VERSION 5.8 ;
BUSBITCHARS "[]" ;
DIVIDERCHAR "/" ;
UNITS
    DATABASE MICRONS 1000 ;
END UNITS

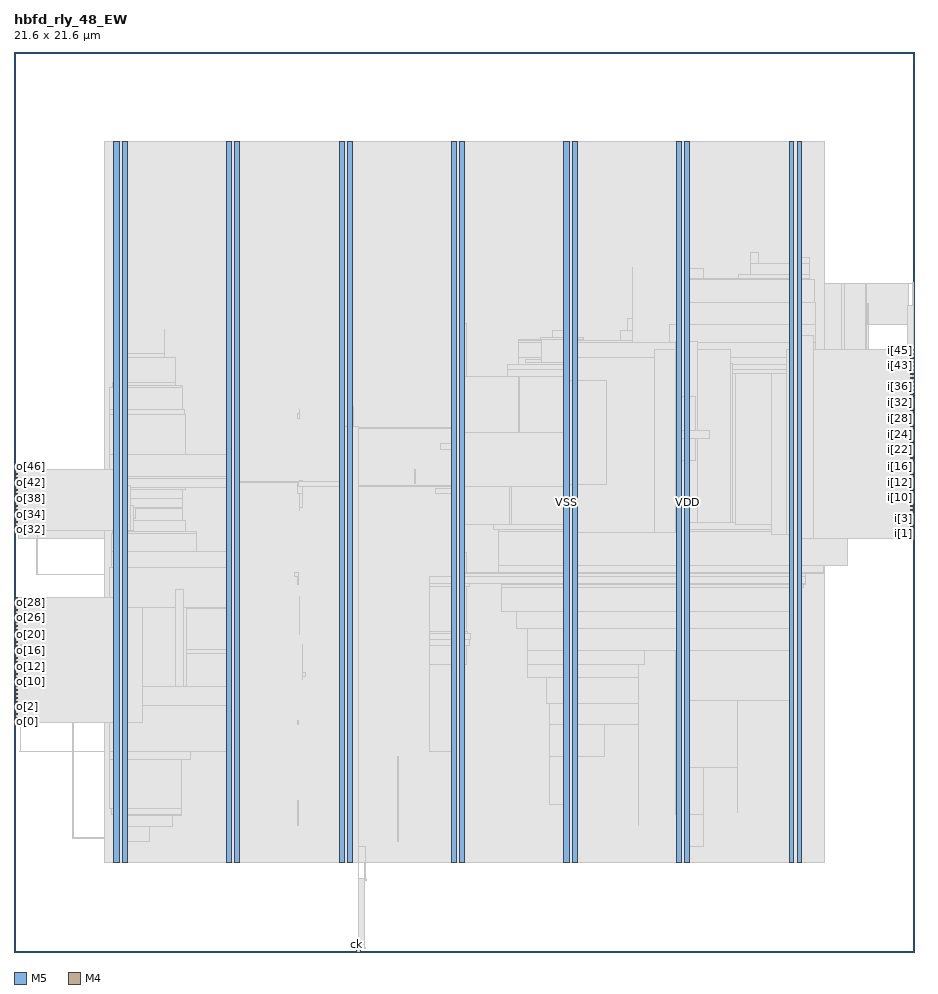
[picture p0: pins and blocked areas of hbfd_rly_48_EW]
MACRO hbfd_rly_48_EW
  FOREIGN hbfd_rly_48_EW 0 0 ;
  CLASS BLOCK ;
  SIZE 21.6 BY 21.6 ;
  PIN ck
    DIRECTION INPUT ;
    USE SIGNAL ;
    PORT
      LAYER M5 ;
        RECT  8.208 0 8.232 0.084 ;
    END
  END ck
  PIN i[0]
    DIRECTION INPUT ;
    USE SIGNAL ;
    PORT
      LAYER M4 ;
        RECT  21.516 9.936 21.6 9.96 ;
    END
  END i[0]
  PIN i[10]
    DIRECTION INPUT ;
    USE SIGNAL ;
    PORT
      LAYER M4 ;
        RECT  21.516 10.896 21.6 10.92 ;
    END
  END i[10]
  PIN i[11]
    DIRECTION INPUT ;
    USE SIGNAL ;
    PORT
      LAYER M4 ;
        RECT  21.516 10.992 21.6 11.016 ;
    END
  END i[11]
  PIN i[12]
    DIRECTION INPUT ;
    USE SIGNAL ;
    PORT
      LAYER M4 ;
        RECT  21.516 11.088 21.6 11.112 ;
    END
  END i[12]
  PIN i[13]
    DIRECTION INPUT ;
    USE SIGNAL ;
    PORT
      LAYER M4 ;
        RECT  21.516 11.184 21.6 11.208 ;
    END
  END i[13]
  PIN i[14]
    DIRECTION INPUT ;
    USE SIGNAL ;
    PORT
      LAYER M4 ;
        RECT  21.516 11.28 21.6 11.304 ;
    END
  END i[14]
  PIN i[15]
    DIRECTION INPUT ;
    USE SIGNAL ;
    PORT
      LAYER M4 ;
        RECT  21.516 11.376 21.6 11.4 ;
    END
  END i[15]
  PIN i[16]
    DIRECTION INPUT ;
    USE SIGNAL ;
    PORT
      LAYER M4 ;
        RECT  21.516 11.472 21.6 11.496 ;
    END
  END i[16]
  PIN i[17]
    DIRECTION INPUT ;
    USE SIGNAL ;
    PORT
      LAYER M4 ;
        RECT  21.516 11.568 21.6 11.592 ;
    END
  END i[17]
  PIN i[18]
    DIRECTION INPUT ;
    USE SIGNAL ;
    PORT
      LAYER M4 ;
        RECT  21.516 11.664 21.6 11.688 ;
    END
  END i[18]
  PIN i[19]
    DIRECTION INPUT ;
    USE SIGNAL ;
    PORT
      LAYER M4 ;
        RECT  21.516 11.76 21.6 11.784 ;
    END
  END i[19]
  PIN i[1]
    DIRECTION INPUT ;
    USE SIGNAL ;
    PORT
      LAYER M4 ;
        RECT  21.516 10.032 21.6 10.056 ;
    END
  END i[1]
  PIN i[20]
    DIRECTION INPUT ;
    USE SIGNAL ;
    PORT
      LAYER M4 ;
        RECT  21.516 11.856 21.6 11.88 ;
    END
  END i[20]
  PIN i[21]
    DIRECTION INPUT ;
    USE SIGNAL ;
    PORT
      LAYER M4 ;
        RECT  21.516 11.952 21.6 11.976 ;
    END
  END i[21]
  PIN i[22]
    DIRECTION INPUT ;
    USE SIGNAL ;
    PORT
      LAYER M4 ;
        RECT  21.516 12.048 21.6 12.072 ;
    END
  END i[22]
  PIN i[23]
    DIRECTION INPUT ;
    USE SIGNAL ;
    PORT
      LAYER M4 ;
        RECT  21.516 12.144 21.6 12.168 ;
    END
  END i[23]
  PIN i[24]
    DIRECTION INPUT ;
    USE SIGNAL ;
    PORT
      LAYER M4 ;
        RECT  21.516 12.24 21.6 12.264 ;
    END
  END i[24]
  PIN i[25]
    DIRECTION INPUT ;
    USE SIGNAL ;
    PORT
      LAYER M4 ;
        RECT  21.516 12.336 21.6 12.36 ;
    END
  END i[25]
  PIN i[26]
    DIRECTION INPUT ;
    USE SIGNAL ;
    PORT
      LAYER M4 ;
        RECT  21.516 12.432 21.6 12.456 ;
    END
  END i[26]
  PIN i[27]
    DIRECTION INPUT ;
    USE SIGNAL ;
    PORT
      LAYER M4 ;
        RECT  21.516 12.528 21.6 12.552 ;
    END
  END i[27]
  PIN i[28]
    DIRECTION INPUT ;
    USE SIGNAL ;
    PORT
      LAYER M4 ;
        RECT  21.516 12.624 21.6 12.648 ;
    END
  END i[28]
  PIN i[29]
    DIRECTION INPUT ;
    USE SIGNAL ;
    PORT
      LAYER M4 ;
        RECT  21.516 12.72 21.6 12.744 ;
    END
  END i[29]
  PIN i[2]
    DIRECTION INPUT ;
    USE SIGNAL ;
    PORT
      LAYER M4 ;
        RECT  21.516 10.128 21.6 10.152 ;
    END
  END i[2]
  PIN i[30]
    DIRECTION INPUT ;
    USE SIGNAL ;
    PORT
      LAYER M4 ;
        RECT  21.516 12.816 21.6 12.84 ;
    END
  END i[30]
  PIN i[31]
    DIRECTION INPUT ;
    USE SIGNAL ;
    PORT
      LAYER M4 ;
        RECT  21.516 12.912 21.6 12.936 ;
    END
  END i[31]
  PIN i[32]
    DIRECTION INPUT ;
    USE SIGNAL ;
    PORT
      LAYER M4 ;
        RECT  21.516 13.008 21.6 13.032 ;
    END
  END i[32]
  PIN i[33]
    DIRECTION INPUT ;
    USE SIGNAL ;
    PORT
      LAYER M4 ;
        RECT  21.516 13.104 21.6 13.128 ;
    END
  END i[33]
  PIN i[34]
    DIRECTION INPUT ;
    USE SIGNAL ;
    PORT
      LAYER M4 ;
        RECT  21.516 13.2 21.6 13.224 ;
    END
  END i[34]
  PIN i[35]
    DIRECTION INPUT ;
    USE SIGNAL ;
    PORT
      LAYER M4 ;
        RECT  21.516 13.296 21.6 13.32 ;
    END
  END i[35]
  PIN i[36]
    DIRECTION INPUT ;
    USE SIGNAL ;
    PORT
      LAYER M4 ;
        RECT  21.516 13.392 21.6 13.416 ;
    END
  END i[36]
  PIN i[37]
    DIRECTION INPUT ;
    USE SIGNAL ;
    PORT
      LAYER M4 ;
        RECT  21.516 13.488 21.6 13.512 ;
    END
  END i[37]
  PIN i[38]
    DIRECTION INPUT ;
    USE SIGNAL ;
    PORT
      LAYER M4 ;
        RECT  21.516 13.584 21.6 13.608 ;
    END
  END i[38]
  PIN i[39]
    DIRECTION INPUT ;
    USE SIGNAL ;
    PORT
      LAYER M4 ;
        RECT  21.516 13.68 21.6 13.704 ;
    END
  END i[39]
  PIN i[3]
    DIRECTION INPUT ;
    USE SIGNAL ;
    PORT
      LAYER M4 ;
        RECT  21.516 10.224 21.6 10.248 ;
    END
  END i[3]
  PIN i[40]
    DIRECTION INPUT ;
    USE SIGNAL ;
    PORT
      LAYER M4 ;
        RECT  21.516 13.776 21.6 13.8 ;
    END
  END i[40]
  PIN i[41]
    DIRECTION INPUT ;
    USE SIGNAL ;
    PORT
      LAYER M4 ;
        RECT  21.516 13.872 21.6 13.896 ;
    END
  END i[41]
  PIN i[42]
    DIRECTION INPUT ;
    USE SIGNAL ;
    PORT
      LAYER M4 ;
        RECT  21.516 13.968 21.6 13.992 ;
    END
  END i[42]
  PIN i[43]
    DIRECTION INPUT ;
    USE SIGNAL ;
    PORT
      LAYER M4 ;
        RECT  21.516 14.064 21.6 14.088 ;
    END
  END i[43]
  PIN i[44]
    DIRECTION INPUT ;
    USE SIGNAL ;
    PORT
      LAYER M4 ;
        RECT  21.516 14.16 21.6 14.184 ;
    END
  END i[44]
  PIN i[45]
    DIRECTION INPUT ;
    USE SIGNAL ;
    PORT
      LAYER M4 ;
        RECT  21.516 14.256 21.6 14.28 ;
    END
  END i[45]
  PIN i[46]
    DIRECTION INPUT ;
    USE SIGNAL ;
    PORT
      LAYER M4 ;
        RECT  21.516 14.352 21.6 14.376 ;
    END
  END i[46]
  PIN i[47]
    DIRECTION INPUT ;
    USE SIGNAL ;
    PORT
      LAYER M4 ;
        RECT  21.516 14.448 21.6 14.472 ;
    END
  END i[47]
  PIN i[4]
    DIRECTION INPUT ;
    USE SIGNAL ;
    PORT
      LAYER M4 ;
        RECT  21.516 10.32 21.6 10.344 ;
    END
  END i[4]
  PIN i[5]
    DIRECTION INPUT ;
    USE SIGNAL ;
    PORT
      LAYER M4 ;
        RECT  21.516 10.416 21.6 10.44 ;
    END
  END i[5]
  PIN i[6]
    DIRECTION INPUT ;
    USE SIGNAL ;
    PORT
      LAYER M4 ;
        RECT  21.516 10.512 21.6 10.536 ;
    END
  END i[6]
  PIN i[7]
    DIRECTION INPUT ;
    USE SIGNAL ;
    PORT
      LAYER M4 ;
        RECT  21.516 10.608 21.6 10.632 ;
    END
  END i[7]
  PIN i[8]
    DIRECTION INPUT ;
    USE SIGNAL ;
    PORT
      LAYER M4 ;
        RECT  21.516 10.704 21.6 10.728 ;
    END
  END i[8]
  PIN i[9]
    DIRECTION INPUT ;
    USE SIGNAL ;
    PORT
      LAYER M4 ;
        RECT  21.516 10.8 21.6 10.824 ;
    END
  END i[9]
  PIN o[0]
    DIRECTION OUTPUT ;
    USE SIGNAL ;
    PORT
      LAYER M4 ;
        RECT  0 5.52 0.084 5.544 ;
    END
  END o[0]
  PIN o[10]
    DIRECTION OUTPUT ;
    USE SIGNAL ;
    PORT
      LAYER M4 ;
        RECT  0 6.48 0.084 6.504 ;
    END
  END o[10]
  PIN o[11]
    DIRECTION OUTPUT ;
    USE SIGNAL ;
    PORT
      LAYER M4 ;
        RECT  0 6.576 0.084 6.6 ;
    END
  END o[11]
  PIN o[12]
    DIRECTION OUTPUT ;
    USE SIGNAL ;
    PORT
      LAYER M4 ;
        RECT  0 6.672 0.084 6.696 ;
    END
  END o[12]
  PIN o[13]
    DIRECTION OUTPUT ;
    USE SIGNAL ;
    PORT
      LAYER M4 ;
        RECT  0 6.768 0.084 6.792 ;
    END
  END o[13]
  PIN o[14]
    DIRECTION OUTPUT ;
    USE SIGNAL ;
    PORT
      LAYER M4 ;
        RECT  0 6.864 0.084 6.888 ;
    END
  END o[14]
  PIN o[15]
    DIRECTION OUTPUT ;
    USE SIGNAL ;
    PORT
      LAYER M4 ;
        RECT  0 6.96 0.084 6.984 ;
    END
  END o[15]
  PIN o[16]
    DIRECTION OUTPUT ;
    USE SIGNAL ;
    PORT
      LAYER M4 ;
        RECT  0 7.056 0.084 7.08 ;
    END
  END o[16]
  PIN o[17]
    DIRECTION OUTPUT ;
    USE SIGNAL ;
    PORT
      LAYER M4 ;
        RECT  0 7.152 0.084 7.176 ;
    END
  END o[17]
  PIN o[18]
    DIRECTION OUTPUT ;
    USE SIGNAL ;
    PORT
      LAYER M4 ;
        RECT  0 7.248 0.084 7.272 ;
    END
  END o[18]
  PIN o[19]
    DIRECTION OUTPUT ;
    USE SIGNAL ;
    PORT
      LAYER M4 ;
        RECT  0 7.344 0.084 7.368 ;
    END
  END o[19]
  PIN o[1]
    DIRECTION OUTPUT ;
    USE SIGNAL ;
    PORT
      LAYER M4 ;
        RECT  0 5.616 0.084 5.64 ;
    END
  END o[1]
  PIN o[20]
    DIRECTION OUTPUT ;
    USE SIGNAL ;
    PORT
      LAYER M4 ;
        RECT  0 7.44 0.084 7.464 ;
    END
  END o[20]
  PIN o[21]
    DIRECTION OUTPUT ;
    USE SIGNAL ;
    PORT
      LAYER M4 ;
        RECT  0 7.536 0.084 7.56 ;
    END
  END o[21]
  PIN o[22]
    DIRECTION OUTPUT ;
    USE SIGNAL ;
    PORT
      LAYER M4 ;
        RECT  0 7.632 0.084 7.656 ;
    END
  END o[22]
  PIN o[23]
    DIRECTION OUTPUT ;
    USE SIGNAL ;
    PORT
      LAYER M4 ;
        RECT  0 7.728 0.084 7.752 ;
    END
  END o[23]
  PIN o[24]
    DIRECTION OUTPUT ;
    USE SIGNAL ;
    PORT
      LAYER M4 ;
        RECT  0 7.824 0.084 7.848 ;
    END
  END o[24]
  PIN o[25]
    DIRECTION OUTPUT ;
    USE SIGNAL ;
    PORT
      LAYER M4 ;
        RECT  0 7.92 0.084 7.944 ;
    END
  END o[25]
  PIN o[26]
    DIRECTION OUTPUT ;
    USE SIGNAL ;
    PORT
      LAYER M4 ;
        RECT  0 8.016 0.084 8.04 ;
    END
  END o[26]
  PIN o[27]
    DIRECTION OUTPUT ;
    USE SIGNAL ;
    PORT
      LAYER M4 ;
        RECT  0 8.112 0.084 8.136 ;
    END
  END o[27]
  PIN o[28]
    DIRECTION OUTPUT ;
    USE SIGNAL ;
    PORT
      LAYER M4 ;
        RECT  0 8.208 0.084 8.232 ;
    END
  END o[28]
  PIN o[29]
    DIRECTION OUTPUT ;
    USE SIGNAL ;
    PORT
      LAYER M4 ;
        RECT  0 8.304 0.084 8.328 ;
    END
  END o[29]
  PIN o[2]
    DIRECTION OUTPUT ;
    USE SIGNAL ;
    PORT
      LAYER M4 ;
        RECT  0 5.712 0.084 5.736 ;
    END
  END o[2]
  PIN o[30]
    DIRECTION OUTPUT ;
    USE SIGNAL ;
    PORT
      LAYER M4 ;
        RECT  0 8.4 0.084 8.424 ;
    END
  END o[30]
  PIN o[31]
    DIRECTION OUTPUT ;
    USE SIGNAL ;
    PORT
      LAYER M4 ;
        RECT  0 8.496 0.084 8.52 ;
    END
  END o[31]
  PIN o[32]
    DIRECTION OUTPUT ;
    USE SIGNAL ;
    PORT
      LAYER M4 ;
        RECT  0 10.128 0.084 10.152 ;
    END
  END o[32]
  PIN o[33]
    DIRECTION OUTPUT ;
    USE SIGNAL ;
    PORT
      LAYER M4 ;
        RECT  0 10.224 0.084 10.248 ;
    END
  END o[33]
  PIN o[34]
    DIRECTION OUTPUT ;
    USE SIGNAL ;
    PORT
      LAYER M4 ;
        RECT  0 10.32 0.084 10.344 ;
    END
  END o[34]
  PIN o[35]
    DIRECTION OUTPUT ;
    USE SIGNAL ;
    PORT
      LAYER M4 ;
        RECT  0 10.416 0.084 10.44 ;
    END
  END o[35]
  PIN o[36]
    DIRECTION OUTPUT ;
    USE SIGNAL ;
    PORT
      LAYER M4 ;
        RECT  0 10.512 0.084 10.536 ;
    END
  END o[36]
  PIN o[37]
    DIRECTION OUTPUT ;
    USE SIGNAL ;
    PORT
      LAYER M4 ;
        RECT  0 10.608 0.084 10.632 ;
    END
  END o[37]
  PIN o[38]
    DIRECTION OUTPUT ;
    USE SIGNAL ;
    PORT
      LAYER M4 ;
        RECT  0 10.704 0.084 10.728 ;
    END
  END o[38]
  PIN o[39]
    DIRECTION OUTPUT ;
    USE SIGNAL ;
    PORT
      LAYER M4 ;
        RECT  0 10.8 0.084 10.824 ;
    END
  END o[39]
  PIN o[3]
    DIRECTION OUTPUT ;
    USE SIGNAL ;
    PORT
      LAYER M4 ;
        RECT  0 5.808 0.084 5.832 ;
    END
  END o[3]
  PIN o[40]
    DIRECTION OUTPUT ;
    USE SIGNAL ;
    PORT
      LAYER M4 ;
        RECT  0 10.896 0.084 10.92 ;
    END
  END o[40]
  PIN o[41]
    DIRECTION OUTPUT ;
    USE SIGNAL ;
    PORT
      LAYER M4 ;
        RECT  0 10.992 0.084 11.016 ;
    END
  END o[41]
  PIN o[42]
    DIRECTION OUTPUT ;
    USE SIGNAL ;
    PORT
      LAYER M4 ;
        RECT  0 11.088 0.084 11.112 ;
    END
  END o[42]
  PIN o[43]
    DIRECTION OUTPUT ;
    USE SIGNAL ;
    PORT
      LAYER M4 ;
        RECT  0 11.184 0.084 11.208 ;
    END
  END o[43]
  PIN o[44]
    DIRECTION OUTPUT ;
    USE SIGNAL ;
    PORT
      LAYER M4 ;
        RECT  0 11.28 0.084 11.304 ;
    END
  END o[44]
  PIN o[45]
    DIRECTION OUTPUT ;
    USE SIGNAL ;
    PORT
      LAYER M4 ;
        RECT  0 11.376 0.084 11.4 ;
    END
  END o[45]
  PIN o[46]
    DIRECTION OUTPUT ;
    USE SIGNAL ;
    PORT
      LAYER M4 ;
        RECT  0 11.472 0.084 11.496 ;
    END
  END o[46]
  PIN o[47]
    DIRECTION OUTPUT ;
    USE SIGNAL ;
    PORT
      LAYER M4 ;
        RECT  0 11.568 0.084 11.592 ;
    END
  END o[47]
  PIN o[4]
    DIRECTION OUTPUT ;
    USE SIGNAL ;
    PORT
      LAYER M4 ;
        RECT  0 5.904 0.084 5.928 ;
    END
  END o[4]
  PIN o[5]
    DIRECTION OUTPUT ;
    USE SIGNAL ;
    PORT
      LAYER M4 ;
        RECT  0 6 0.084 6.024 ;
    END
  END o[5]
  PIN o[6]
    DIRECTION OUTPUT ;
    USE SIGNAL ;
    PORT
      LAYER M4 ;
        RECT  0 6.096 0.084 6.12 ;
    END
  END o[6]
  PIN o[7]
    DIRECTION OUTPUT ;
    USE SIGNAL ;
    PORT
      LAYER M4 ;
        RECT  0 6.192 0.084 6.216 ;
    END
  END o[7]
  PIN o[8]
    DIRECTION OUTPUT ;
    USE SIGNAL ;
    PORT
      LAYER M4 ;
        RECT  0 6.288 0.084 6.312 ;
    END
  END o[8]
  PIN o[9]
    DIRECTION OUTPUT ;
    USE SIGNAL ;
    PORT
      LAYER M4 ;
        RECT  0 6.384 0.084 6.408 ;
    END
  END o[9]
  PIN rs
    DIRECTION INPUT ;
    USE SIGNAL ;
    PORT
      LAYER M5 ;
        RECT  8.304 0 8.328 0.084 ;
    END
  END rs
  PIN VDD
    DIRECTION INOUT ;
    USE POWER ;
    PORT
      LAYER M5 ;
        RECT  18.792 2.151 18.912 19.449 ;
        RECT  16.092 2.151 16.212 19.449 ;
        RECT  13.392 2.151 13.512 19.449 ;
        RECT  10.692 2.151 10.812 19.449 ;
        RECT  7.992 2.151 8.112 19.449 ;
        RECT  5.292 2.151 5.412 19.449 ;
        RECT  2.592 2.151 2.712 19.449 ;
    END
  END VDD
  PIN VSS
    DIRECTION INOUT ;
    USE GROUND ;
    PORT
      LAYER M5 ;
        RECT  18.6 2.137 18.72 19.463 ;
        RECT  15.9 2.137 16.02 19.463 ;
        RECT  13.2 2.137 13.32 19.463 ;
        RECT  10.5 2.137 10.62 19.463 ;
        RECT  7.8 2.137 7.92 19.463 ;
        RECT  5.1 2.137 5.22 19.463 ;
        RECT  2.4 2.137 2.52 19.463 ;
    END
  END VSS
  # OT_OBS_CLOSED layer=M5 d_um=1.536 added=5
  OBS
    LAYER RVTN ;
     RECT  2.16 2.16 19.44 2.295 ;
     RECT  2.16 2.565 19.44 2.835 ;
     RECT  2.16 3.105 19.44 3.375 ;
     RECT  2.16 3.645 19.44 3.915 ;
     RECT  2.16 4.185 19.44 4.455 ;
     RECT  2.16 4.725 19.44 4.995 ;
     RECT  2.16 5.265 19.44 5.535 ;
     RECT  2.16 5.805 19.44 6.075 ;
     RECT  2.16 6.345 19.44 6.615 ;
     RECT  2.16 6.885 19.44 7.155 ;
     RECT  2.16 7.425 19.44 7.695 ;
     RECT  2.16 7.965 19.44 8.235 ;
     RECT  2.16 8.505 19.44 8.775 ;
     RECT  2.16 9.045 19.44 9.315 ;
     RECT  2.16 9.585 19.44 9.855 ;
     RECT  2.16 10.125 19.44 10.395 ;
     RECT  2.16 10.665 19.44 10.935 ;
     RECT  2.16 11.205 19.44 11.475 ;
     RECT  2.16 11.745 19.44 12.015 ;
     RECT  2.16 12.285 19.44 12.555 ;
     RECT  2.16 12.825 19.44 13.095 ;
     RECT  2.16 13.365 19.44 13.635 ;
     RECT  2.16 13.905 19.44 14.175 ;
     RECT  2.16 14.445 19.44 14.715 ;
     RECT  2.16 14.985 19.44 15.255 ;
     RECT  2.16 15.525 19.44 15.795 ;
     RECT  2.16 16.065 19.44 16.335 ;
     RECT  2.16 16.605 19.44 16.875 ;
     RECT  2.16 17.145 19.44 17.415 ;
     RECT  2.16 17.685 19.44 17.955 ;
     RECT  2.16 18.225 19.44 18.495 ;
     RECT  2.16 18.765 19.44 19.035 ;
     RECT  2.16 19.305 19.44 19.44 ;
    LAYER RVTP ;
     RECT  2.16 2.295 19.44 2.565 ;
     RECT  2.16 2.835 19.44 3.105 ;
     RECT  2.16 3.375 19.44 3.645 ;
     RECT  2.16 3.915 19.44 4.185 ;
     RECT  2.16 4.455 19.44 4.725 ;
     RECT  2.16 4.995 19.44 5.265 ;
     RECT  2.16 5.535 19.44 5.805 ;
     RECT  2.16 6.075 19.44 6.345 ;
     RECT  2.16 6.615 19.44 6.885 ;
     RECT  2.16 7.155 19.44 7.425 ;
     RECT  2.16 7.695 19.44 7.965 ;
     RECT  2.16 8.235 19.44 8.505 ;
     RECT  2.16 8.775 19.44 9.045 ;
     RECT  2.16 9.315 19.44 9.585 ;
     RECT  2.16 9.855 19.44 10.125 ;
     RECT  2.16 10.395 19.44 10.665 ;
     RECT  2.16 10.935 19.44 11.205 ;
     RECT  2.16 11.475 19.44 11.745 ;
     RECT  2.16 12.015 19.44 12.285 ;
     RECT  2.16 12.555 19.44 12.825 ;
     RECT  2.16 13.095 19.44 13.365 ;
     RECT  2.16 13.635 19.44 13.905 ;
     RECT  2.16 14.175 19.44 14.445 ;
     RECT  2.16 14.715 19.44 14.985 ;
     RECT  2.16 15.255 19.44 15.525 ;
     RECT  2.16 15.795 19.44 16.065 ;
     RECT  2.16 16.335 19.44 16.605 ;
     RECT  2.16 16.875 19.44 17.145 ;
     RECT  2.16 17.415 19.44 17.685 ;
     RECT  2.16 17.955 19.44 18.225 ;
     RECT  2.16 18.495 19.44 18.765 ;
     RECT  2.16 19.035 19.44 19.305 ;
    LAYER M1 ;
     RECT  2.16 2.151 19.44 19.449 ;
    LAYER M2 ;
     RECT  0.463 6.084 0.535 6.444 ;
     RECT  0.103 9.936 0.535 9.954 ;
     RECT  1.399 2.736 2.16 2.754 ;
     RECT  0.139 4.806 2.16 4.824 ;
     RECT  0.535 5.616 2.16 6.444 ;
     RECT  0.535 7.326 2.16 7.794 ;
     RECT  0.535 9.054 2.16 9.072 ;
     RECT  0.535 9.936 2.16 10.224 ;
     RECT  2.16 2.151 19.44 19.449 ;
     RECT  19.44 9.288 19.859 16.056 ;
     RECT  19.859 13.878 19.931 16.056 ;
     RECT  19.859 9.288 19.967 13.05 ;
     RECT  19.967 9.288 20.003 9.306 ;
     RECT  19.967 10.098 20.003 13.05 ;
     RECT  20.003 10.98 20.435 13.05 ;
     RECT  19.931 14.184 20.435 16.056 ;
     RECT  20.435 12.528 20.471 13.05 ;
     RECT  20.435 15.03 20.471 16.056 ;
     RECT  20.471 12.528 20.507 12.924 ;
     RECT  20.003 10.098 20.543 10.116 ;
     RECT  20.435 10.98 20.543 11.574 ;
     RECT  20.507 12.87 20.543 12.888 ;
     RECT  20.435 14.184 21.479 14.202 ;
     RECT  20.471 15.066 21.479 16.056 ;
     RECT  20.543 11.52 21.515 11.538 ;
     RECT  21.479 15.066 21.515 15.084 ;
     RECT  21.487 13.41 21.587 13.428 ;
     RECT  21.479 16.038 21.587 16.056 ;
    LAYER M3 ;
     RECT  8.424 1.723 8.442 2.143 ;
     RECT  2.415 2.143 2.505 2.413 ;
     RECT  5.115 2.143 5.205 2.413 ;
     RECT  10.515 2.143 10.605 2.413 ;
     RECT  13.215 2.143 13.305 2.413 ;
     RECT  15.915 2.143 16.005 2.413 ;
     RECT  18.615 2.143 18.705 2.413 ;
     RECT  7.815 2.143 8.442 2.525 ;
     RECT  15.915 2.413 16.197 2.533 ;
     RECT  2.415 2.413 2.697 2.641 ;
     RECT  2.415 2.641 3.258 3.001 ;
     RECT  2.415 3.001 3.798 3.271 ;
     RECT  2.415 3.271 4.014 3.307 ;
     RECT  15.915 2.533 16.542 3.307 ;
     RECT  2.34 3.307 4.014 3.451 ;
     RECT  13.215 2.413 13.497 3.541 ;
     RECT  6.804 3.037 6.822 3.641 ;
     RECT  15.876 3.307 16.542 4.423 ;
     RECT  17.352 3.343 17.37 4.423 ;
     RECT  2.304 3.451 4.014 4.621 ;
     RECT  9.216 2.641 9.234 4.685 ;
     RECT  12.852 3.541 13.497 4.693 ;
     RECT  2.304 4.621 4.23 4.801 ;
     RECT  5.115 2.413 5.397 4.801 ;
     RECT  10.515 2.413 10.797 4.801 ;
     RECT  12.852 4.693 14.166 5.467 ;
     RECT  14.976 3.037 14.994 5.467 ;
     RECT  6.804 5.467 6.822 5.567 ;
     RECT  0.144 4.801 0.162 5.611 ;
     RECT  1.404 2.731 1.422 5.645 ;
     RECT  2.304 4.801 5.397 5.909 ;
     RECT  12.852 5.467 14.994 5.971 ;
     RECT  0.144 5.611 0.558 6.029 ;
     RECT  15.876 4.423 17.37 6.043 ;
     RECT  18.615 2.413 18.897 6.043 ;
     RECT  0.468 6.029 0.558 6.509 ;
     RECT  12.78 5.971 14.994 6.583 ;
     RECT  6.912 6.547 6.93 6.619 ;
     RECT  2.34 5.909 5.397 6.667 ;
     RECT  6.912 6.619 7.002 6.719 ;
     RECT  9.972 4.801 10.797 6.889 ;
     RECT  12.312 6.583 14.994 6.889 ;
     RECT  2.304 6.667 5.397 7.051 ;
     RECT  12.312 6.889 15.138 7.231 ;
     RECT  15.876 6.043 18.897 7.231 ;
     RECT  0.468 6.509 0.522 7.243 ;
     RECT  2.268 7.051 5.397 7.259 ;
     RECT  0.324 7.243 0.522 7.321 ;
     RECT  9.972 6.889 10.854 7.357 ;
     RECT  0.324 7.321 0.558 7.373 ;
     RECT  6.912 6.719 6.93 7.385 ;
     RECT  9.972 7.357 10.926 7.501 ;
     RECT  9.972 7.501 10.962 7.655 ;
     RECT  9.972 7.655 10.89 7.7 ;
     RECT  12.312 7.231 18.897 7.771 ;
     RECT  0.54 7.373 0.558 8.045 ;
     RECT  12.06 7.771 18.897 8.167 ;
     RECT  0.144 8.107 0.162 8.285 ;
     RECT  6.84 7.627 6.858 8.537 ;
     RECT  11.7 8.167 18.897 8.743 ;
     RECT  9.972 7.7 10.854 8.779 ;
     RECT  11.7 8.743 18.954 8.815 ;
     RECT  9.972 8.779 10.926 8.851 ;
     RECT  11.7 8.815 18.99 8.851 ;
     RECT  9.972 8.851 18.99 9.005 ;
     RECT  6.804 8.815 6.822 9.013 ;
     RECT  10.515 9.005 18.99 9.085 ;
     RECT  6.732 9.013 6.822 9.113 ;
     RECT  10.515 9.085 19.422 9.113 ;
     RECT  2.304 7.259 5.397 9.239 ;
     RECT  11.628 9.113 19.422 9.283 ;
     RECT  10.515 9.113 10.854 9.581 ;
     RECT  2.34 9.239 5.397 9.617 ;
     RECT  0.54 9.049 0.558 9.931 ;
     RECT  2.34 9.617 4.374 10.049 ;
     RECT  2.376 10.049 4.374 10.085 ;
     RECT  11.628 9.283 19.998 10.093 ;
     RECT  0.108 9.931 0.558 10.123 ;
     RECT  11.628 10.093 20.538 10.129 ;
     RECT  0.108 10.123 0.666 10.253 ;
     RECT  0.108 10.253 0.558 10.349 ;
     RECT  2.376 10.085 4.122 10.355 ;
     RECT  10.515 9.581 10.797 10.561 ;
     RECT  11.52 10.129 20.538 10.561 ;
     RECT  0.144 10.349 0.558 10.637 ;
     RECT  6.84 10.597 6.858 10.669 ;
     RECT  0.144 10.637 0.162 10.829 ;
     RECT  21.42 10.651 21.438 10.829 ;
     RECT  2.376 10.355 4.05 10.891 ;
     RECT  6.84 10.669 6.93 11.011 ;
     RECT  10.515 10.561 20.538 11.011 ;
     RECT  2.304 10.891 4.05 11.101 ;
     RECT  10.116 11.011 20.538 11.129 ;
     RECT  2.304 11.101 4.122 11.137 ;
     RECT  5.115 9.617 5.397 11.137 ;
     RECT  6.804 11.011 6.93 11.273 ;
     RECT  6.84 11.273 6.93 11.309 ;
     RECT  2.304 11.137 5.397 11.371 ;
     RECT  2.268 11.371 5.397 11.408 ;
     RECT  21.492 11.467 21.51 11.543 ;
     RECT  9.612 11.245 9.63 11.579 ;
     RECT  7.815 2.525 8.097 11.641 ;
     RECT  2.304 11.408 5.397 11.939 ;
     RECT  10.515 11.129 20.538 12.055 ;
     RECT  21.42 11.995 21.438 12.173 ;
     RECT  10.224 12.055 20.538 12.209 ;
     RECT  2.304 11.939 4.122 12.893 ;
     RECT  10.515 12.209 20.538 12.893 ;
     RECT  6.804 12.793 6.858 12.929 ;
     RECT  2.304 12.893 4.086 13.019 ;
     RECT  6.84 12.929 6.858 13.019 ;
     RECT  7.815 11.641 8.154 13.091 ;
     RECT  21.492 13.387 21.51 13.405 ;
     RECT  2.304 13.019 4.05 13.559 ;
     RECT  10.515 12.893 20.502 13.559 ;
     RECT  2.376 13.559 4.05 13.595 ;
     RECT  2.376 13.595 3.87 13.667 ;
     RECT  11.844 13.559 20.502 13.973 ;
     RECT  11.844 13.973 19.314 14.099 ;
     RECT  21.492 13.405 21.582 14.155 ;
     RECT  2.415 13.667 3.87 14.279 ;
     RECT  12.096 14.099 19.314 14.279 ;
     RECT  2.415 14.279 3.618 14.369 ;
     RECT  20.412 13.973 20.502 14.441 ;
     RECT  12.096 14.279 19.242 14.639 ;
     RECT  12.096 14.639 14.85 14.675 ;
     RECT  12.096 14.675 13.662 14.711 ;
     RECT  12.636 14.711 13.662 14.747 ;
     RECT  12.924 14.747 13.497 14.909 ;
     RECT  14.544 14.675 14.85 14.909 ;
     RECT  3.6 14.369 3.618 14.945 ;
     RECT  15.732 14.639 19.242 15.053 ;
     RECT  20.448 14.441 20.502 15.053 ;
     RECT  10.515 13.559 10.854 15.089 ;
     RECT  14.724 14.909 14.85 15.215 ;
     RECT  21.456 14.155 21.582 15.521 ;
     RECT  20.484 15.053 20.502 15.557 ;
     RECT  15.915 15.053 19.242 15.593 ;
     RECT  21.564 15.521 21.582 16.061 ;
     RECT  15.915 15.593 19.206 16.133 ;
     RECT  15.915 16.133 19.098 16.169 ;
     RECT  17.388 16.169 19.098 16.259 ;
     RECT  15.915 16.169 16.542 16.403 ;
     RECT  14.832 15.215 14.85 16.439 ;
     RECT  17.676 16.259 19.098 16.529 ;
     RECT  18.615 16.529 19.098 16.673 ;
     RECT  17.676 16.529 17.874 16.799 ;
     RECT  2.415 14.369 2.697 19.187 ;
     RECT  5.115 11.939 5.397 19.187 ;
     RECT  7.815 13.091 8.097 19.187 ;
     RECT  10.515 15.089 10.797 19.187 ;
     RECT  13.215 14.909 13.497 19.187 ;
     RECT  15.915 16.403 16.197 19.187 ;
     RECT  18.615 16.673 18.897 19.187 ;
     RECT  2.415 19.187 2.505 19.457 ;
     RECT  5.115 19.187 5.205 19.457 ;
     RECT  7.815 19.187 7.905 19.457 ;
     RECT  10.515 19.187 10.605 19.457 ;
     RECT  13.215 19.187 13.305 19.457 ;
     RECT  15.915 19.187 16.005 19.457 ;
     RECT  18.615 19.187 18.705 19.457 ;
    LAYER M4 ;
     RECT  0.06 10.128 2.401 11.592 ;
     RECT  0.06 5.52 2.408 8.52 ;
     RECT  2.401 10.128 2.408 11.688 ;
     RECT  2.408 2.148 2.512 19.452 ;
     RECT  2.512 2.418 2.704 19.182 ;
     RECT  2.704 5.52 2.729 8.52 ;
     RECT  2.704 10.128 2.801 11.208 ;
     RECT  2.801 10.128 2.873 10.728 ;
     RECT  2.873 10.416 2.909 10.68 ;
     RECT  2.729 5.52 3.089 8.28 ;
     RECT  3.089 6.384 3.877 8.28 ;
     RECT  2.909 10.656 4.025 10.68 ;
     RECT  3.877 6.384 4.061 8.712 ;
     RECT  4.061 6.384 4.133 8.28 ;
     RECT  4.133 6.384 5.108 7.176 ;
     RECT  4.133 8.256 5.108 8.28 ;
     RECT  5.108 2.148 5.212 19.452 ;
     RECT  5.212 2.418 5.404 19.182 ;
     RECT  5.404 11.28 6.829 11.304 ;
     RECT  6.829 11.184 7.808 11.304 ;
     RECT  7.808 2.148 7.912 19.452 ;
     RECT  7.912 2.148 8.104 19.182 ;
     RECT  8.101 0.096 8.291 0.216 ;
     RECT  8.291 0.096 8.435 0.12 ;
     RECT  8.369 1.728 8.453 1.752 ;
     RECT  8.104 11.184 10.508 11.208 ;
     RECT  8.104 12.576 10.508 12.6 ;
     RECT  10.508 2.148 10.612 19.452 ;
     RECT  10.612 2.418 10.804 19.182 ;
     RECT  10.804 10.272 12.013 11.304 ;
     RECT  10.804 12.576 12.013 13.08 ;
     RECT  12.013 10.272 12.044 13.08 ;
     RECT  12.044 10.272 12.053 13.8 ;
     RECT  12.053 10.416 12.131 13.8 ;
     RECT  12.265 14.16 12.661 14.232 ;
     RECT  12.131 10.416 13.208 12.6 ;
     RECT  12.661 14.16 13.208 14.712 ;
     RECT  13.208 2.148 13.312 19.452 ;
     RECT  13.312 2.418 13.504 19.182 ;
     RECT  13.504 10.08 15.361 14.28 ;
     RECT  15.361 10.08 15.865 14.472 ;
     RECT  15.865 10.08 15.908 14.664 ;
     RECT  15.908 2.148 16.012 19.452 ;
     RECT  16.012 2.418 16.204 19.182 ;
     RECT  16.204 10.32 16.409 14.664 ;
     RECT  16.409 10.32 17.201 14.472 ;
     RECT  17.201 10.32 17.237 14.136 ;
     RECT  17.237 10.32 17.305 13.896 ;
     RECT  17.305 10.272 18.169 13.896 ;
     RECT  18.169 10.032 18.529 13.896 ;
     RECT  18.529 10.032 18.608 14.472 ;
     RECT  18.608 2.148 18.712 19.452 ;
     RECT  18.712 2.418 18.904 19.182 ;
     RECT  18.904 9.936 19.181 14.808 ;
     RECT  19.181 9.936 21.564 14.472 ;
    LAYER M5 ;
     RECT  8.208 0.016 8.328 0.085 ;
     RECT  8.112 0.085 8.424 0.227 ;
     RECT  8.256 0.227 8.424 1.763 ;
     RECT  8.256 1.763 8.28 2.137 ;
     RECT  2.4 2.137 2.52 2.151 ;
     RECT  5.1 2.137 5.22 2.151 ;
     RECT  10.5 2.137 10.62 2.151 ;
     RECT  13.2 2.137 13.32 2.151 ;
     RECT  15.9 2.137 16.02 2.151 ;
     RECT  18.6 2.137 18.72 2.151 ;
     RECT  0.144 7.189 0.168 7.379 ;
     RECT  11.904 10.261 11.928 11.171 ;
     RECT  13.2 2.151 13.512 11.221 ;
     RECT  15.9 2.151 16.212 11.797 ;
     RECT  15.9 11.797 16.344 12.325 ;
     RECT  15.9 12.325 16.68 12.515 ;
     RECT  7.8 2.137 8.28 12.611 ;
     RECT  15.9 12.515 16.344 13.331 ;
     RECT  13.2 11.221 14.232 13.715 ;
     RECT  12.096 12.469 12.12 13.811 ;
     RECT  2.4 2.151 2.712 19.449 ;
     RECT  5.1 2.151 5.412 19.449 ;
     RECT  7.8 12.611 8.112 19.449 ;
     RECT  10.5 2.151 10.812 19.449 ;
     RECT  13.2 13.715 13.512 19.449 ;
     RECT  15.9 13.331 16.212 19.449 ;
     RECT  18.6 2.151 18.912 19.449 ;
     RECT  2.4 19.449 2.52 19.463 ;
     RECT  5.1 19.449 5.22 19.463 ;
     RECT  7.8 19.449 7.92 19.463 ;
     RECT  10.5 19.449 10.62 19.463 ;
     RECT  13.2 19.449 13.32 19.463 ;
     RECT  15.9 19.449 16.02 19.463 ;
     RECT  18.6 19.449 18.72 19.463 ;
     RECT  10.812 10.261 11.904 11.171 ;
     RECT  11.928 10.261 13.2 11.171 ;
     RECT  10.812 11.171 13.2 12.469 ;
     RECT  10.812 12.469 12.096 13.811 ;
     RECT  12.12 12.469 13.2 13.811 ;
  END
END hbfd_rly_48_EW
END LIBRARY
